One B-rep face of a CAD part: STEP entity #520.
In plain terms, the planar face has unit normal (1, 0, 0).
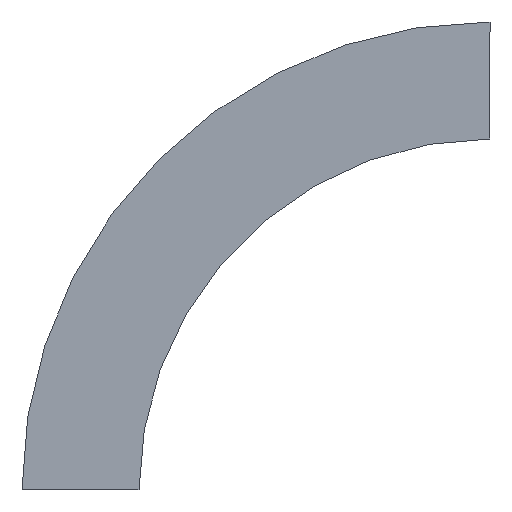
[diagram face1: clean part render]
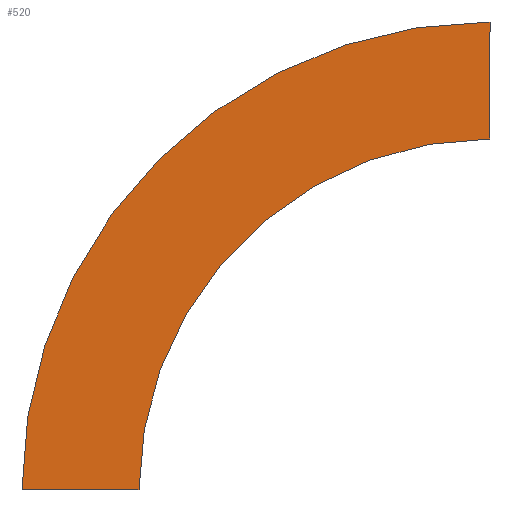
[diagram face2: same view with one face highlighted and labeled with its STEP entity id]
Its self-contained STEP definition (entity closure, numbers rounded to 3 decimals):
#29 = CARTESIAN_POINT ( 'NONE',  ( 0., -300., 0. ) ) ;
#35 = DIRECTION ( 'NONE',  ( 1., 0., 0. ) ) ;
#44 = CARTESIAN_POINT ( 'NONE',  ( 0., 0., 0. ) ) ;
#50 = CARTESIAN_POINT ( 'NONE',  ( 0., 100., 0. ) ) ;
#57 = EDGE_CURVE ( 'NONE', #126, #562, #295, .T. ) ;
#73 = CIRCLE ( 'NONE', #277, 400. ) ;
#81 = ORIENTED_EDGE ( 'NONE', *, *, #447, .T. ) ;
#86 = CARTESIAN_POINT ( 'NONE',  ( 0., 0., 0. ) ) ;
#95 = DIRECTION ( 'NONE',  ( 0., 0., 1. ) ) ;
#112 = ORIENTED_EDGE ( 'NONE', *, *, #289, .T. ) ;
#115 = EDGE_CURVE ( 'NONE', #562, #571, #327, .T. ) ;
#119 = CARTESIAN_POINT ( 'NONE',  ( 0., -300., 0. ) ) ;
#126 = VERTEX_POINT ( 'NONE', #44 ) ;
#128 = AXIS2_PLACEMENT_3D ( 'NONE', #86, #533, #568 ) ;
#173 = DIRECTION ( 'NONE',  ( 0., 1., 0. ) ) ;
#216 = ORIENTED_EDGE ( 'NONE', *, *, #57, .F. ) ;
#245 = VECTOR ( 'NONE', #318, 1000. ) ;
#247 = EDGE_LOOP ( 'NONE', ( #81, #349, #216, #112 ) ) ;
#277 = AXIS2_PLACEMENT_3D ( 'NONE', #29, #494, #452 ) ;
#289 = EDGE_CURVE ( 'NONE', #126, #518, #509, .T. ) ;
#295 = CIRCLE ( 'NONE', #440, 300. ) ;
#297 = CARTESIAN_POINT ( 'NONE',  ( 0., 0., 0. ) ) ;
#318 = DIRECTION ( 'NONE',  ( 0., 1., 0. ) ) ;
#323 = CARTESIAN_POINT ( 'NONE',  ( 0., -300., 300. ) ) ;
#327 = LINE ( 'NONE', #323, #485 ) ;
#349 = ORIENTED_EDGE ( 'NONE', *, *, #115, .F. ) ;
#396 = CARTESIAN_POINT ( 'NONE',  ( 0., -300., 400. ) ) ;
#440 = AXIS2_PLACEMENT_3D ( 'NONE', #119, #35, #173 ) ;
#447 = EDGE_CURVE ( 'NONE', #518, #571, #73, .T. ) ;
#452 = DIRECTION ( 'NONE',  ( 0., 1., 0. ) ) ;
#456 = FACE_OUTER_BOUND ( 'NONE', #247, .T. ) ;
#481 = PLANE ( 'NONE',  #128 ) ;
#485 = VECTOR ( 'NONE', #95, 1000. ) ;
#494 = DIRECTION ( 'NONE',  ( 1., 0., 0. ) ) ;
#509 = LINE ( 'NONE', #297, #245 ) ;
#518 = VERTEX_POINT ( 'NONE', #50 ) ;
#520 = ADVANCED_FACE ( 'NONE', ( #456 ), #481, .T. ) ;
#533 = DIRECTION ( 'NONE',  ( 1., 0., 0. ) ) ;
#562 = VERTEX_POINT ( 'NONE', #573 ) ;
#568 = DIRECTION ( 'NONE',  ( 0., 0., -1. ) ) ;
#571 = VERTEX_POINT ( 'NONE', #396 ) ;
#573 = CARTESIAN_POINT ( 'NONE',  ( 0., -300., 300. ) ) ;
